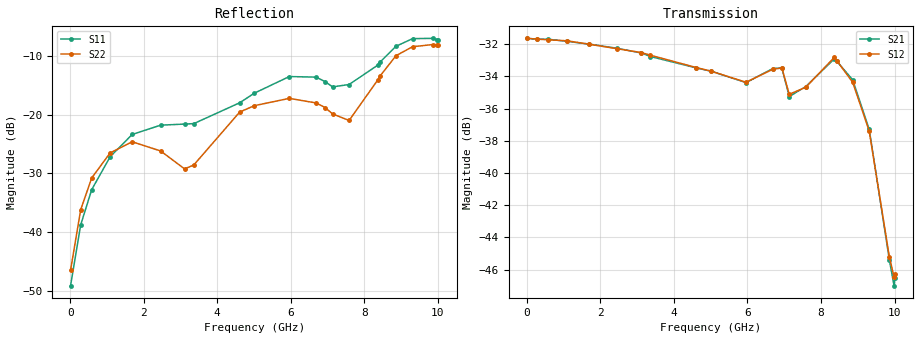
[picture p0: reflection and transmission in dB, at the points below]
! Device ID: PE43704
! Dir: z:\PE43704\PE43704_Char_1_20130516\PE43704\AMB\3p400V\30p75dB
! Serial: 14
! Insertion: A
! Impedance: 50 ohm
! Temp: Amb
! VDD: 3.400V
! Attenuation Step: 30.75dB
! IDD: 1.139756e-01mA
#  Hz  S  RI  R  50
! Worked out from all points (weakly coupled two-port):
!   401 points, 10 MHz to 10.01 GHz, reference 50 ohm
!   highest |S21| = -31.62 dB at 10 MHz (marker M1); lowest = -47.0 dB at 9.985 GHz (marker M2)
!   lowest |S11| = -49.2 dB at 10 MHz (marker M3), VSWR 1.01, Z = 50.3 + j0.0381 ohm
!   |S11| at or under -10 dB: start of sweep to 8.566 GHz
!   |S22| runs from -46.5 to -7.9 dB; largest |S21 - S12| = 0.00063
!   S11 on the Smith chart (normalised r, x): 10 MHz: 1.01, +0.00; 4.61 GHz: 0.79, +0.08; 8.435 GHz: 0.76, +0.46; 9.31 GHz: 0.51, +0.52; 10.01 GHz: 0.44, +0.31
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1e7  0.00346 0.000379  0.0262 -5.26e-05  0.0262 -2.32e-05  -0.0047 0.00048
2.85e8  0.000527 0.0115  0.026 -0.00174  0.026 -0.00172  -0.00667 0.014
5.85e8  -0.00985 0.0208  0.0258 -0.00348  0.0257 -0.00342  -0.0153 0.0246
1.085e9  -0.0374 0.0229  0.0249 -0.00617  0.025 -0.00619  -0.0378 0.0285
1.685e9  -0.0678 0.00661  0.0234 -0.00924  0.0234 -0.00919  -0.0573 0.014
2.46e9  -0.0801 -0.0165  0.0209 -0.0126  0.0208 -0.0126  -0.0492 -0.000571
3.11e9  -0.0818 -0.0169  0.0183 -0.0149  0.0184 -0.0149  -0.0334 0.009
3.36e9  -0.0836 -0.0107  0.0171 -0.0154  0.0173 -0.0155  -0.0332 0.0171
4.61e9  -0.1168 0.0499  0.0124 -0.0172  0.0125 -0.0172  -0.0863 0.0613
5.01e9  -0.136 0.0712  0.0117 -0.0171  0.0117 -0.0171  -0.1056 0.057
5.96e9  -0.1862 0.1029  0.0083 -0.0172  0.0082 -0.0173  -0.1313 0.044
6.685e9  -0.1869 0.0963  0.00732 -0.0198  0.00725 -0.0197  -0.1216 0.0351
6.935e9  -0.1692 0.0915  0.00423 -0.0208  0.00411 -0.0208  -0.1084 0.0398
7.135e9  -0.1544 0.0794  0.00358 -0.0169  0.00356 -0.0172  -0.0914 0.0452
7.585e9  -0.1264 0.1308  0.00414 -0.0181  0.00414 -0.018  -0.0585 0.068
8.36e9  -0.0591 0.2589  -0.00316 -0.0224  -0.00271 -0.0227  -0.0717 0.1845
8.435e9  -0.0604 0.2782  -0.00423 -0.0218  -0.00413 -0.0219  -0.0819 0.2006
8.86e9  -0.1005 0.3723  -0.0097 -0.0169  -0.0097 -0.0165  -0.1442 0.2863
9.31e9  -0.1826 0.4095  -0.00977 -0.00958  -0.00954 -0.00957  -0.2354 0.3012
9.86e9  -0.3032 0.3334  -0.00308 -0.00438  -0.00319 -0.00445  -0.3518 0.1884
9.985e9  -0.3234 0.2963  -0.00115 -0.00432  -0.00124 -0.0046  -0.3688 0.1437
1.001e10  -0.3289 0.2881  -0.000825 -0.00465  -0.00121 -0.00471  -0.3724 0.1356
